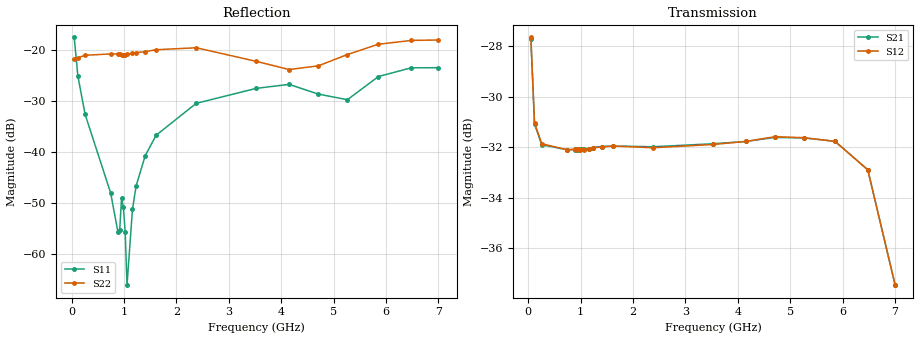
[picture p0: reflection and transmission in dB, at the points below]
! Integrated Device Technology
! Corporate Headquarters
! 6024 Silver Creek Valley Road
! San Jose, CA 95138  USA
! Phone:  1-408-284-8200
! Toll Free:  1-800-223-1366
! Webpage:  http://www.idt.com/
! Timing and RF Division
! 515 Groton Road, Suite 102
! Westford, MA 01886-6024
! Device:  F2258
! Description: Voltage Variable RF Attenuator
! Frequency:  50.0 -  6000.00 MHz
! Package:  3x3 mm Thin QFN Plastic Package: 16 pin
! Ports:  2 RF, 2 DC
!  Pin  1  = NC
!  Pin  2  = NC
!  Pin  3  = RF2  = Port 2
!  Pin  4  = GND
!  Pin  5  = Vdd
!  Pin  6  = NC
!  Pin  7  = VCTRL
!  Pin  8  = NC
!  Pin  9  = GND
!  Pin 10  = RF1  = Port 1
!  Pin 11  = NC
!  Pin 12  = NC
!  Pin 13  = NC
!  Pin 14  = NC
!  Pin 15  = NC
!  Pin 16  = NC
! Vcntrl:  1.740 Volts
! Vdd:  +3.300 Volts
! Current:  1.158 mA
! Data:  The device was measured on a the F2258 evaluation board which has
!  individual transmission lines to the RF pins.  Data was collected
!  using a calibrated network analyzer.  The evaluation board was
!  de-embedded using a TRL calibration technique.
!  The reference plane is the edge of the package pin.
! Misc:  SN 10
!  Action Tracker AT0285
! Date Measured:  2014-12-10
! Date:  2016-01-13  MJV
! Note:
!  Integrated Device Technology supplies this data as a sample of measured
!  data at the package pin for this product.  Your particular data for this
!  product may vary.
!  Data was taken at 25 degrees C.
!  Integrated Device Technology reserves the right to change this data at anytime.
!Freq_(GHz)  S11M_(dB)  S11P_(deg)  S21M_(dB)  S21P_(deg)  S12M_(dB)  S12P_(deg)  S22M_(dB)  S22P_(deg)
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# GHz S dB R 50
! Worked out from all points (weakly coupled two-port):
!   201 points, 50 MHz to 7 GHz, reference 50 ohm
!   highest |S21| = -27.69 dB at 50 MHz (marker M1); lowest = -37.5 dB at 7 GHz (marker M2)
!   lowest |S11| = -66.2 dB at 1.058 GHz (marker M3), VSWR 1.00, Z = 50 + j0.0306 ohm
!   |S11| at or under -10 dB: start of sweep to end of sweep
!   |S22| runs from -24.2 to -18.0 dB; largest |S21 - S12| = 0.00025
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0.05  -17.53 -110.4  -27.69 -55.9  -27.64 -55.8  -21.74 -68.5
0.1195  -25.10 -105.9  -31.08 -29.5  -31.03 -29.5  -21.53 -21.7
0.2585  -32.66 -109.6  -31.90 -15.8  -31.86 -15.8  -21.04 -10.2
0.745  -48.07 -133.7  -32.10 -10.1  -32.10 -10.1  -20.78 -8.0
0.884  -55.73 168.9  -32.09 -10.2  -32.08 -10.2  -20.78 -9.4
0.91875  -55.27 143.8  -32.08 -10.3  -32.09 -10.2  -20.79 -9.7
0.9535  -49.10 -154.6  -32.09 -10.3  -32.08 -10.3  -21.05 -8.7
0.98825  -50.80 -168.0  -32.08 -10.3  -32.09 -10.3  -21.05 -9.5
1.023  -55.83 -179.8  -32.07 -10.4  -32.08 -10.4  -20.93 -9.9
1.05775  -66.18 141.3  -32.06 -10.5  -32.09 -10.5  -20.88 -9.8
1.162  -51.26 52.5  -32.05 -10.8  -32.06 -10.8  -20.69 -10.6
1.2315  -46.69 36.8  -32.01 -11.2  -32.02 -11.2  -20.50 -11.2
1.40525  -40.75 29.5  -31.97 -12.3  -31.99 -12.3  -20.34 -12.0
1.61375  -36.74 29.9  -31.95 -13.8  -31.95 -13.8  -19.95 -14.0
2.37825  -30.48 46.5  -31.98 -19.0  -32.02 -19.0  -19.57 -18.0
3.525  -27.54 90.9  -31.86 -27.8  -31.89 -27.7  -22.24 -27.3
4.1505  -26.76 104.6  -31.77 -33.2  -31.77 -33.2  -23.84 -42.1
4.7065  -28.66 95.2  -31.61 -38.4  -31.58 -38.5  -23.12 -51.6
5.2625  -29.77 53.1  -31.63 -44.5  -31.62 -44.5  -20.90 -54.0
5.85325  -25.22 29.0  -31.76 -53.9  -31.77 -53.8  -18.88 -53.2
6.47875  -23.51 40.9  -32.89 -68.1  -32.90 -68.0  -18.13 -71.2
7  -23.48 84.0  -37.46 -68.5  -37.47 -68.3  -18.04 -123.7
